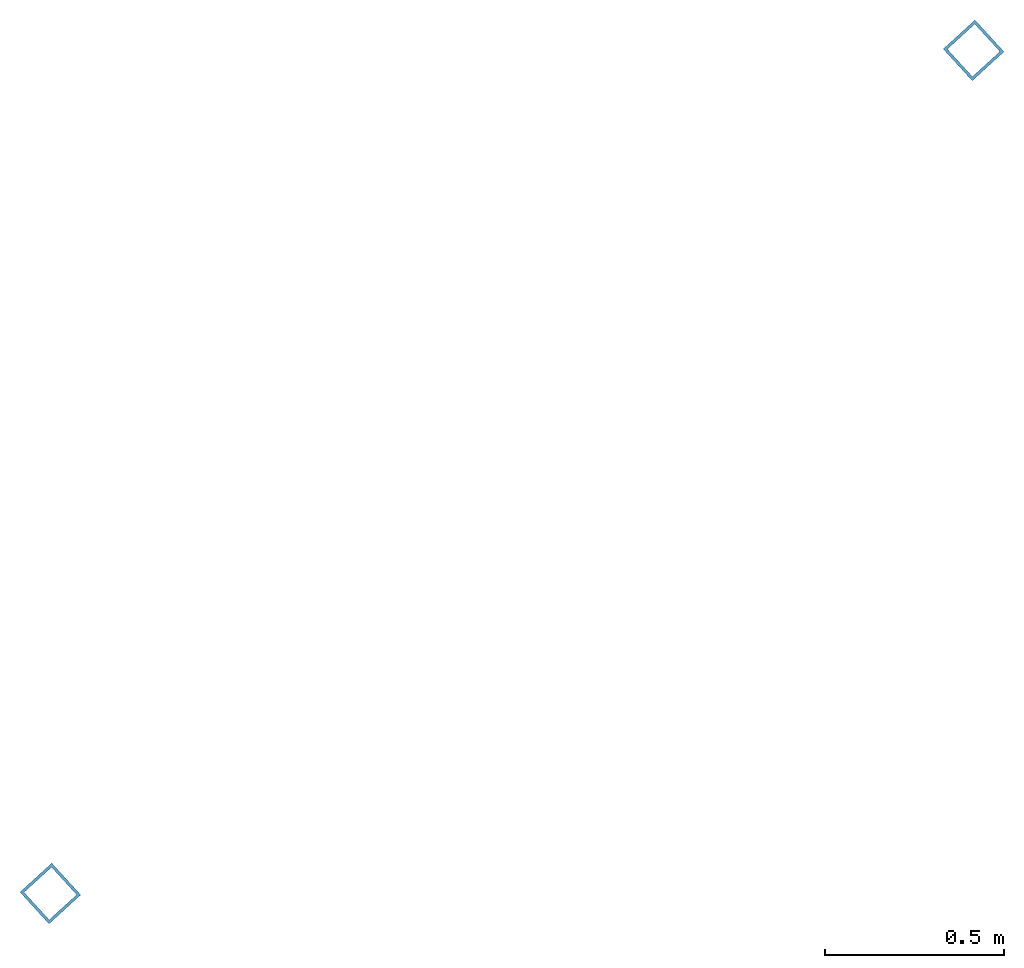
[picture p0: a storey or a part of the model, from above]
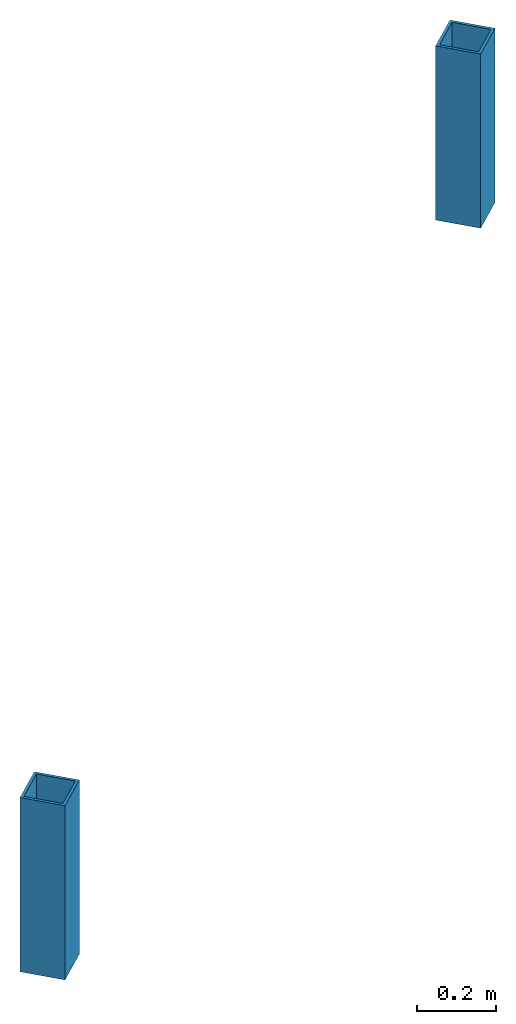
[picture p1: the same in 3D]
Properties of the parts of a building model (IFC2X3)

# File
Description: ViewDefinition [CoordinationView_V2.0, QuantityTakeOffAddOnView]
File name: zv001-a-200-1-0003.ifc (Edited by Naviate Simple BIM 2022 version 6)
Time: 2026-01-09T13:08:05+01:00
Written by: ODA SDAI 24.12
Made in: Autodesk Revit 25.4.30.30 (ENU) - IFC 25.4.0.27

# IfcProject, 10001574
LongName: ENZV Kommersielt areal innland (KAI); Phase: Hovedprosjekt: 01.12.2018

# IfcSite (3)
RefElevation: 0 mm
Name | RefLatitude | RefLongitude | Pset_ProductRequirements, Category
ENZV | 59, 54, 57, 601318 | 10, 44, 59, 999999 | Identity Data - Inventarnr.: ZV001; Building Name: ZV001; CQIncludeDoorSwing: no; CQIncludeRoomNumber: no; CQIncludeRoomNumberWindows: no; CQIncludeWindowSwing: no; Workset: Project Info; Organization Description: BIM 360://Avinor - Stavanger lufthavn/ENZV_ARK_bygg A.rvt; Prosjekt: Stavanger lufthavn, Sola; Text - 02_IfcSite: STAVANGER LUFTHAVN; 01_Modellfil: zv001-a-200-1-0003.rvt; Prosjektleder: Livar Husveg; Tiltaket gjelder: Kommersielt areal innland, KAI; Other - Project Number: 10001574; CQDoorSwingCodes: Left=V;Right=H;notMirrored =L;mirrored =R; Project Issue Date: Tilbudsprosjekt: 22.07.2018; CQWindowSwingCodes: Left=Rettv.;Right=Speilv.; Category: Project Information; Project Address: Enter address here; CQPhaseFilter: Existing:True;New Construction:True;Fase 2.0:True;Fase 3.0:True;Fase 3.9:True;Fase 4.0:True;Fase 5.1:True;Fase 5.2:True;Fase 5.3:True;Fase 5.4:True;Fase 5.9:True;Fase 5.10:True;Fase plot tegninger:True;Fase 6.0:True;; CQIncludeTemporaryDoors: no; Project Name: ENZV Kommersielt areal innland (KAI); Project Status: Hovedprosjekt: 01.12.2018; Tiltakshavers navn: Livar Husveg
2 x Default | 42, 12, 46, 804504 | -71, -1, -58, -789672 | Project Information

# IfcBuilding (3)
Name | NumberOfStoreys | Pset_ProductRequirements, Category
ZV001 | 8 | LongName: ZV001; Identity Data - Inventarnr.: ZV001; Building Name: ZV001; CQIncludeDoorSwing: no; CQIncludeRoomNumber: no; CQIncludeRoomNumberWindows: no; CQIncludeWindowSwing: no; Workset: Project Info; Organization Description: BIM 360://Avinor - Stavanger lufthavn/ENZV_ARK_bygg A.rvt; Prosjekt: Stavanger lufthavn, Sola; Text - 02_IfcSite: STAVANGER LUFTHAVN; 01_Modellfil: zv001-a-200-1-0003.rvt; Prosjektleder: Livar Husveg; Tiltaket gjelder: Kommersielt areal innland, KAI; Other - Project Number: 10001574; CQDoorSwingCodes: Left=V;Right=H;notMirrored =L;mirrored =R; Project Issue Date: Tilbudsprosjekt: 22.07.2018; CQWindowSwingCodes: Left=Rettv.;Right=Speilv.; Category: Project Information; Project Address: Enter address here; CQPhaseFilter: Existing:True;New Construction:True;Fase 2.0:True;Fase 3.0:True;Fase 3.9:True;Fase 4.0:True;Fase 5.1:True;Fase 5.2:True;Fase 5.3:True;Fase 5.4:True;Fase 5.9:True;Fase 5.10:True;Fase plot tegninger:True;Fase 6.0:True;; CQIncludeTemporaryDoors: no; Project Name: ENZV Kommersielt areal innland (KAI); Project Status: Hovedprosjekt: 01.12.2018; Tiltakshavers navn: Livar Husveg
2 x  | 5 | Project Information

# IfcBuildingStorey: Level:8mm Nivåhode Lokale Koter (3)
In: ZV001
Identity Data - Structural: no; Building Story: yes; Workset: Shared Levels and Grids
Graphics(Type) - Line Pattern: Centre; Color: 0; Symbol at End 1 Default: no; Symbol at End 2 Default: yes; Line Weight: 1; Symbol: View - Nivåhode1 : Nivåhode Trekant 2
Identity Data(Type) - Workset: Level Types; Type Name: 8mm Nivåhode Lokale Koter
Constraints(Type) - Elevation Base: Project Base Point
Other - Type Id: 305; Category: Levels; Family and Type: Level: 8mm Nivåhode Lokale Koter; Family: Level; Type: 8mm Nivåhode Lokale Koter
Other(Type) - Category: Levels; Family Name: Level
Phasing - Fagkode: ARK
Name | LongName = Identity Data, Name | Elevation (mm) = Constraints, Elevation (mm) | Pset_AirSideSystemInformation, Name | Pset_AirSideSystemInformation, sets with these values | Etasjekoder | Computation Height (mm)
H01 | H01 | 5100 | H01 | 2 | H01 | 1200
H02 | H02 | 9300 | H02 | 2 | H02 | 0
H03 | H03 | 13200 |  |  | H05 | 0 | Pset_ProductRequirements - Name: H03; sets with these values: 2

# IfcBuildingStorey: Level:_VERKIS-level (6)
Pset_ProductRequirements - Category: Levels
Name | LongName = Pset_AirSideSystemInformation, Name = Pset_ProductRequirements, Name | Elevation (mm)
2 x 1. ETASJE | 1. ETASJE | 5100
2 x 2. ETASJE | 2. ETASJE | 9300
2 x 3. ETASJE | 3. ETASJE | 13200

# IfcBeam: IPE-Beams:IPE220 (4)
Type - Pset_BeamCommon - IsExternal: no; LoadBearing: yes; Reference: IPE220
Type - Pset_ProductRequirements - Category: Structural Framing
Type - Pset_QuantityTakeOff - Reference: IPE220
Type - Pset_ReinforcementBarPitchOfBeam - Reference: IPE220
ePset_LocationTool - Splitting: RESULT
ePset_SimplebimBasicQuantities - Width (Simplebim): 110 mm; Height (Simplebim): 220 mm; Length (Simplebim): 5090 mm
ePset_Simplebim - Assembly Level: Leaf
Pset_QuantityTakeOff - sets with these values: 2
Name (IPE-Beams:IPE220:...) | In | Weight, as steel (Simplebim) (kg) | Volume, net (Simplebim) (m3) | Area, sides, net (Simplebim) (m2)
1845180 | 3. ETASJE | 102.266 | 0.0130276 | 3.58357
1845180 | 3. ETASJE | 106.293 | 0.0135405 | 3.50207
1844115 | 2. ETASJE | 102.266 | 0.0130276 | 3.58357
1844115 | 2. ETASJE | 106.293 | 0.0135405 | 3.50207

# IfcColumn: NO_Column_Steel_Hollow Rectangular:RHS 120x120x8 (8)
Type - PredefinedType: COLUMN; Material: Stål - S355J
Type - Pset_ColumnCommon - IsExternal: no; LoadBearing: yes; Reference: RHS 120x120x8
Type - Pset_ProductRequirements - Category: Structural Columns
Type - Pset_QuantityTakeOff - Reference: RHS 120x120x8
Type - Pset_ReinforcementBarPitchOfColumn - Reference: RHS 120x120x8
ePset_SimplebimBasicQuantities - Width (Simplebim): 120 mm; Depth (Simplebim): 120 mm
ePset_Simplebim - Assembly Level: Leaf
Pset_QuantityTakeOff - sets with these values: 2
Name (NO_Column_Steel_Hollow Rectangular:RHS 120x120x8:...) | In | Weight, as steel (Simplebim) (kg) | Volume, net (Simplebim) (m3) | Height (Simplebim) (mm) | Area, sides, net (Simplebim) (m2) | Splitting
1844919 | 2. ETASJE | 112.313 | 0.0143073 | 3992 | 3.57683 | ORIGINAL
1844921 | 2. ETASJE | 112.313 | 0.0143073 | 3992 | 3.57683 | ORIGINAL
1844919 | 2. ETASJE | 107.059 | 0.0136381 | 3992 | 3.41167 | ORIGINAL
1844921 | 2. ETASJE | 107.059 | 0.0136381 | 3992 | 3.41167 | ORIGINAL
1840977 | 1. ETASJE | 15.1926 | 0.00193536 | 540 | 0.48384 | RESULT
1840979 | 1. ETASJE | 15.1926 | 0.00193536 | 540 | 0.48384 | RESULT
1840977 | 1. ETASJE | 14.482 | 0.00184484 | 540 | 0.461498 | RESULT
1840979 | 1. ETASJE | 14.482 | 0.00184484 | 540 | 0.461498 | RESULT

# IfcColumn: Søyle Betong Sirkulær:350 (3)
In: H02
Type - PredefinedType: COLUMN; Material: Betong Plasstøpt - B35
Type - Other - Category: Structural Columns; Family Name: Søyle Betong Sirkulær; k1: 3.14159
Type - Dimensions - D: 350 mm; Perimeter: 1099.56 mm
Type - Identity Data - Type Name: 350; URL: www.cad-q.no; Workset: Family : Structural Columns : Søyle Betong Sirkulær
Type - Structural - Section Shape: 0
Type - Pset_ColumnCommon - LoadBearing: yes
Phasing - Phase Created: Fase 1 - Som bygget
Pset_QuantityTakeOff - Reference: 350; sets with these values: 2
Pset_ColumnCommon - IsExternal: no; Reference: 350
Identity Data - Has Association: yes; Workset: Workset1
Dimensions - Volume: 0.322292 m3; Length: 3350 mm
Other - Family and Type: Søyle Betong Sirkulær: 350; Type Id: 414188; Family: Søyle Betong Sirkulær; Type: 350
ePset_LocationTool - Splitting: ORIGINAL
ePset_SimplebimBasicQuantities - Height (Simplebim): 3350 mm; Depth (Simplebim): 350 mm; Width (Simplebim): 350 mm; Volume, net (Simplebim): 0.320674 m3; Weight, as steel (Simplebim): 2517.29 kg; Area, sides, net (Simplebim): 3.67884 m2
Structural - Rebar Cover - Top Face: Rebar Cover 1 <25 mm>; Rebar Cover - Other Faces: Rebar Cover 1 <25 mm>; Rebar Cover - Bottom Face: Rebar Cover 1 <25 mm>
ePset_Simplebim - Assembly Level: Leaf
Materials and Finishes - Structural Material: Betong Plasstøpt - B35
Constraints - Top Offset: -550 mm; Room Bounding: yes; Base Offset: 0 mm; Moves With Grids: yes; Base Level: H02; Level: H02; Top Level: H03; Column Style: Vertical
BaseQuantities - NetVolume: 0.322292 m3; OuterSurfaceArea: 3.68352 m2; CrossSectionArea: 0.0961984 m2; Length: 3350 mm; GrossVolume: 0.322265 m3
Name (Søyle Betong Sirkulær:350:...) | Column Location Mark
548730 | L-164
548803 | L-162
548818 | L-160

# IfcColumn: Søyle Betong Sirkulær:450 (3)
In: H01
Type - PredefinedType: COLUMN; Material: Betong Plasstøpt - B35
Type - Other - Category: Structural Columns; Family Name: Søyle Betong Sirkulær; k1: 3.14159
Type - Dimensions - D: 450 mm; Perimeter: 1413.72 mm
Type - Identity Data - Type Name: 450; URL: www.cad-q.no; Workset: Family : Structural Columns : Søyle Betong Sirkulær
Type - Structural - Section Shape: 0
Type - Pset_ColumnCommon - LoadBearing: yes
Phasing - Phase Created: Fase 1 - Som bygget
Identity Data - Has Association: yes; Workset: Workset1
Other - Family and Type: Søyle Betong Sirkulær: 450; Type Id: 958864; Family: Søyle Betong Sirkulær; Type: 450
Structural - Rebar Cover - Top Face: Rebar Cover 1 <25 mm>; Rebar Cover - Other Faces: Rebar Cover 1 <25 mm>; Rebar Cover - Bottom Face: Rebar Cover 1 <25 mm>
Constraints - Room Bounding: yes; Moves With Grids: yes; Level: H01; Base Level: H01; Top Level: H02; Column Style: Vertical
ePset_LocationTool - Splitting: RESULT
ePset_Simplebim - Assembly Level: Leaf
Materials and Finishes - Structural Material: Betong Plasstøpt - B35
ePset_SimplebimBasicQuantities - Area, sides, net (Simplebim): 0.635365 m2; Volume, net (Simplebim): 0.0712066 m3; Weight, as steel (Simplebim): 558.972 kg; Height (Simplebim): 450 mm; Width (Simplebim): 450 mm; Depth (Simplebim): 450 mm
Pset_ColumnCommon - IsExternal: no; Reference: 450
Pset_ReinforcementBarPitchOfColumn - Reference: 450; sets with these values: 2
Name (Søyle Betong Sirkulær:450:...) | Column Location Mark
958997 | L-160
959023 | L-164
959010 | L-162

# IfcSlab: Floor:Standard 550mm (2)
Type - PredefinedType: FLOOR; Material: <Unnamed> 550 mm
Type - Other - Category: Floors; Family Name: Floor
Type - Construction - Function: Interior; Default Thickness: 550 mm
Type - Graphics - Coarse Scale Fill Color: 0
Type - Identity Data - Type Name: Standard 550mm; Workset: Floor Types
Type - Analytical Properties - Absorptance: 0.1; Roughness: 1
Other - Type: Standard 550mm; Type Id: 388455; Family and Type: Floor: Standard 550mm; Family: Floor
Pset_QuantityTakeOff - Reference: Standard 550mm; sets with these values: 2
Pset_SlabCommon - LoadBearing: no; IsExternal: no; Reference: Standard 550mm
ePset_LocationTool - Splitting: RESULT
Identity Data - Has Association: no; Workset: Workset1
Phasing - Phase Created: Fase 1 - Som bygget
ePset_SimplebimBasicQuantities - Area, sides, net (Simplebim): 28.5518 m2; Perimeter (Simplebim): 51912.3 mm; Area, top, net (Simplebim): 115.915 m2; Volume, net (Simplebim): 63.7533 m3; Area, largest surface, net (Simplebim): 115.915 m2; Thickness (Simplebim): 550 mm
Constraints - Related to Mass: no; Room Bounding: yes
ePset_Simplebim - Assembly Level: Leaf
Structural - Structural: no
Name (Floor:Standard 550mm:...) | In | Level
566137 | H02 | H02
632864 | H03 | H03

# IfcSlab: Floor:Standard 560mm, Floor:Standard 560mm:3043193
In: H02
Type - PredefinedType: FLOOR; Material: <Unnamed> 560 mm
Type - Other - Category: Floors; Family Name: Floor
Type - Construction - Function: Interior; Default Thickness: 560 mm
Type - Graphics - Coarse Scale Fill Color: 0
Type - Identity Data - Type Name: Standard 560mm; Workset: Floor Types
Type - Analytical Properties - Absorptance: 0.1; Roughness: 1
Pset_ReinforcementBarPitchOfSlab - Reference: Standard 560mm; sets with these values: 2
Pset_SlabCommon - LoadBearing: no; IsExternal: no; Reference: Standard 560mm
Identity Data - Has Association: no; Workset: Workset1
Other - Type Id: 638814; Family and Type: Floor: Standard 560mm; Type: Standard 560mm; Family: Floor
Phasing - Phase Created: Fase 1 - Som bygget
ePset_SimplebimBasicQuantities - Area, top, net (Simplebim): 115.915 m2; Area, largest surface, net (Simplebim): 115.915 m2; Thickness (Simplebim): 560 mm; Perimeter (Simplebim): 51912.3 mm; Volume, net (Simplebim): 64.9124 m3; Area, sides, net (Simplebim): 29.0709 m2
Constraints - Related to Mass: no; Room Bounding: yes; Level: H02
ePset_Simplebim - Assembly Level: Leaf
Structural - Structural: no
ePset_LocationTool - Splitting: RESULT

# IfcSlab: Floor:Ståldekke 128 (2)
In: 3. ETASJE
Type - PredefinedType: FLOOR; Material: NO_Metall - Stål(2) 128 mm
Type - Pset_ElementShading - Roughness: 304.8 mm
Type - Pset_ProductRequirements - Category: Floors
Type - Pset_QuantityTakeOff - Reference: Ståldekke 128
Type - Pset_ReinforcementBarPitchOfSlab - Description: Ståldekke; Reference: Ståldekke 128
Type - Pset_SlabCommon - Reference: Ståldekke 128; IsExternal: no
ePset_SimplebimBasicQuantities - Area, sides, net (Simplebim): 1.3372 m2; Area, top, net (Simplebim): 0.686474 m2; Volume, net (Simplebim): 0.0878688 m3; Perimeter (Simplebim): 10446.9 mm; Area, largest surface, net (Simplebim): 0.686475 m2; Thickness (Simplebim): 128 mm
Pset_SlabCommon - LoadBearing: yes
ePset_LocationTool - Splitting: RESULT
ePset_Simplebim - Assembly Level: Leaf

# IfcWall: Basic Wall:IV Eks-96 mm_70 mm stålstender+1*13 mm gips hver side (2)
In: H02
Type - PredefinedType: STANDARD; Material: Vegg 13 mm, Vegg 70 mm, Vegg 13 mm
Type - Other - Category: Walls; Family Name: Basic Wall
Type - Construction - Function: Exterior; Width: 96 mm; Wrapping at Inserts: Do not wrap
Type - Graphics - Coarse Scale Fill Color: 12632256; Coarse Scale Fill Pattern: <Solid fill>
Type - Identity Data - Type Name: IV Eks-96 mm_70 mm stålstender+1*13 mm gips hver side; Workset: Wall Types; Type Mark: Eksisterende
Type - Analytical Properties - Absorptance: 0.1; Roughness: 1
Phasing - Phase Created: Fase 1 - Som bygget
Pset_WallCommon - IsExternal: yes; ExtendToStructure: no; LoadBearing: no; Reference: IV Eks-96 mm_70 mm stålstender+1*13 mm gips hver side
ePset_LocationTool - Splitting: RESULT
Constraints - Top Constraint: Up to level: H03; Base is Attached: no; Related to Mass: no; Room Bounding: yes; Top is Attached: no; Base Constraint: H02; Location Line: Finish Face: Interior
Cross-Section Definition - Cross-Section: Vertical
Structural - Structural Usage: Non-bearing; Structural: no
Pset_QuantityTakeOff - Reference: IV Eks-96 mm_70 mm stålstender+1*13 mm gips hver side; sets with these values: 2
Identity Data - Workset: Workset1
ePset_Simplebim - Assembly Level: Leaf
Other - Family: Basic Wall; Type: IV Eks-96 mm_70 mm stålstender+1*13 mm gips hver side; Family and Type: Basic Wall: IV Eks-96 mm_70 mm stålstender+1*13 mm gips hver side; Type Id: 1363173
Name (Basic Wall:IV Eks-96 mm_70 mm stålstender+1*13 mm gips hver side:...) | Area, largest surface, net (Simplebim) (m2) | Volume, net (Simplebim) (m3)
510428 | 6.9048 | 0.662858 | ePset_SimplebimBasicQuantities - Area, side, net, smaller (Simplebim): 6.90474 m2; Area, side, gross, AABB (Simplebim): 6.90435 m2; Area, side, net, average (Simplebim): 6.90477 m2; Area, side, gross, average (Simplebim): 9.03587 m2; Area, side, net, larger (Simplebim): 6.9048 m2; Area, side, gross, smaller (Simplebim): 9.03584 m2; Thickness (Simplebim): 96 mm; Length (Simplebim): 2061 mm; Height (Simplebim): 3350 mm; Area, side, gross, larger (Simplebim): 9.0359 m2
510471 | 1.43029 | 0.0899561 | Dimensions - Keep Concentric: yes; Graphics - Center Mark Visible: no

# IfcWallStandardCase: Basic Wall:IV Eks-96 mm_70 mm stålstender+1*13 mm gips hver side, Basic Wall:IV Eks-96 mm_70 mm stålstender+1*13 mm gips hver side:510463
In: H02
Type - PredefinedType: STANDARD; Material: Vegg 13 mm, Vegg 70 mm, Vegg 13 mm
Type - Other - Category: Walls; Family Name: Basic Wall
Type - Construction - Function: Exterior; Width: 96 mm; Wrapping at Inserts: Do not wrap
Type - Graphics - Coarse Scale Fill Color: 12632256; Coarse Scale Fill Pattern: <Solid fill>
Type - Identity Data - Type Name: IV Eks-96 mm_70 mm stålstender+1*13 mm gips hver side; Workset: Wall Types; Type Mark: Eksisterende
Type - Analytical Properties - Absorptance: 0.1; Roughness: 1
Phasing - Phase Created: Fase 1 - Som bygget
ePset_SimplebimBasicQuantities - Area, side, net, larger (Simplebim): 35.4719 m2; Area, side, gross, larger (Simplebim): 35.4719 m2; Area, largest surface, net (Simplebim): 35.4719 m2; Area, side, net, average (Simplebim): 35.4718 m2; Area, side, gross, average (Simplebim): 35.4718 m2; Area, side, gross, AABB (Simplebim): 35.4719 m2; Area, side, net, smaller (Simplebim): 35.4718 m2; Area, side, gross, smaller (Simplebim): 35.4718 m2; Volume, net (Simplebim): 3.4053 m3; Length (Simplebim): 10588.6 mm; Thickness (Simplebim): 96 mm; Height (Simplebim): 3350 mm
Dimensions - Area: 35.4719 m2; Length: 10636.6 mm; Volume: 3.4053 m3
Pset_WallCommon - IsExternal: yes; ExtendToStructure: no; LoadBearing: no; Reference: IV Eks-96 mm_70 mm stålstender+1*13 mm gips hver side
Constraints - Unconnected Height: 3350 mm; Top Offset: -550 mm; Top Constraint: Up to level: H03; Base Extension Distance: 0 mm; Base is Attached: no; Base Offset: 0 mm; Related to Mass: no; Room Bounding: yes; Top Extension Distance: 0 mm; Top is Attached: no; Base Constraint: H02; Location Line: Finish Face: Interior
Cross-Section Definition - Cross-Section: Vertical
Structural - Structural Usage: Non-bearing; Structural: no
ePset_LocationTool - Splitting: ORIGINAL
Pset_QuantityTakeOff - Reference: IV Eks-96 mm_70 mm stålstender+1*13 mm gips hver side; sets with these values: 2
Identity Data - Workset: Workset1
ePset_Simplebim - Assembly Level: Leaf
Other - Family: Basic Wall; Type: IV Eks-96 mm_70 mm stålstender+1*13 mm gips hver side; Family and Type: Basic Wall: IV Eks-96 mm_70 mm stålstender+1*13 mm gips hver side; Type Id: 1363173
BaseQuantities - GrossSideArea: 35.4719 m2; NetSideArea: 35.4719 m2; GrossFootprintArea: 1.01651 m2; NetVolume: 3.4053 m3; Length: 10588.6 mm; Width: 96 mm; Height: 3350 mm; GrossVolume: 3.4053 m3

# IfcWallStandardCase: Basic Wall:Standard - 150mm (3)
In: H02
Type - PredefinedType: STANDARD; Material: Vegg 150 mm
Type - Other - Category: Walls; Family Name: Basic Wall
Type - Construction - Function: Exterior; Width: 150 mm; Wrapping at Inserts: Do not wrap
Type - Graphics - Coarse Scale Fill Color: 12632256; Coarse Scale Fill Pattern: <Solid fill>
Type - Identity Data - Type Name: Standard - 150mm; Workset: Wall Types
Type - Analytical Properties - Absorptance: 0.1; Roughness: 1
Phasing - Phase Created: Fase 1 - Som bygget
ePset_LocationTool - Splitting: ORIGINAL
Constraints - Unconnected Height: 3350 mm; Base Extension Distance: 0 mm; Base is Attached: no; Base Offset: 0 mm; Related to Mass: no; Room Bounding: yes; Top Extension Distance: 0 mm; Top is Attached: no; Base Constraint: H02; Location Line: Finish Face: Interior
Cross-Section Definition - Cross-Section: Vertical
Structural - Structural Usage: Non-bearing; Structural: no
Identity Data - Workset: Workset1
ePset_SimplebimBasicQuantities - Thickness (Simplebim): 150 mm; Height (Simplebim): 3350 mm
Other - Family: Basic Wall; Family and Type: Basic Wall: Standard - 150mm; Type Id: 129062; Type: Standard - 150mm
Pset_QuantityTakeOff - Reference: Standard - 150mm; sets with these values: 2
ePset_Simplebim - Assembly Level: Leaf
Pset_WallCommon - IsExternal: yes; ExtendToStructure: no; LoadBearing: no; Reference: Standard - 150mm
BaseQuantities - Width: 150 mm; Height: 3350 mm
Name (Basic Wall:Standard - 150mm:...) | Top Offset (mm) | Area, side, gross, AABB (Simplebim) (m2) = Area, side, net, smaller (Simplebim) (m2) = Area, side, gross, smaller (Simplebim) (m2) = Area, side, net, larger (Simplebim) (m2) = Area, side, gross, larger (Simplebim) (m2) = Area, side, gross, average (Simplebim) (m2) = Area, side, net, average (Simplebim) (m2) = Area, largest surface, net (Simplebim) (m2) | Volume, net (Simplebim) (m3) | Length (Simplebim) (mm) = BaseQuantities, Length (mm) | Area (m2) = NetSideArea (m2) = GrossSideArea (m2) | Dimensions, Length (mm) | Volume (m3) = NetVolume (m3) | GrossVolume (m3) | GrossFootprintArea (m2)
531061 | -550 | 29.3913 | 4.40869 | 8773.51 | 29.3913 | 8746.51 | 4.40869 | 4.40869 | 1.31603 | Constraints - Top Constraint: Up to level: H03
901176 | 0 | 9.2929 | 1.39394 | 2774 | 9.2929 | 2849 | 1.39393 | 1.39394 | 0.4161
2475116 | 0 | 9.2929 | 1.39394 | 2774 | 9.29289 | 2849 | 1.39393 | 1.39393 | 0.4161

# IfcWallStandardCase: Basic Wall:Standard - 152mm, Basic Wall:Standard - 152mm:510175
In: H02
Type - PredefinedType: STANDARD; Material: Vegg 152 mm
Type - Other - Category: Walls; Family Name: Basic Wall
Type - Construction - Function: Exterior; Width: 152 mm; Wrapping at Inserts: Do not wrap
Type - Graphics - Coarse Scale Fill Color: 12632256; Coarse Scale Fill Pattern: <Solid fill>
Type - Identity Data - Type Name: Standard - 152mm; Workset: Wall Types
Type - Analytical Properties - Absorptance: 0.1; Roughness: 1
Phasing - Phase Created: Fase 1 - Som bygget
Pset_ReinforcementBarPitchOfWall - Reference: Standard - 152mm; sets with these values: 2
Constraints - Unconnected Height: 3350 mm; Top Offset: -550 mm; Top Constraint: Up to level: H03; Base Extension Distance: 0 mm; Base is Attached: no; Base Offset: 0 mm; Related to Mass: no; Room Bounding: yes; Top Extension Distance: 0 mm; Top is Attached: no; Base Constraint: H02; Location Line: Finish Face: Interior
Cross-Section Definition - Cross-Section: Vertical
Structural - Structural Usage: Non-bearing; Structural: no
Dimensions - Length: 6599.96 mm; Area: 22.6191 m2; Volume: 3.4381 m3
Identity Data - Workset: Workset1
ePset_LocationTool - Splitting: ORIGINAL
ePset_Simplebim - Assembly Level: Leaf
Other - Type: Standard - 152mm; Type Id: 452378; Family: Basic Wall; Family and Type: Basic Wall: Standard - 152mm
ePset_SimplebimBasicQuantities - Area, side, gross, AABB (Simplebim): 22.6191 m2; Area, side, net, smaller (Simplebim): 22.6191 m2; Area, side, gross, larger (Simplebim): 22.6191 m2; Area, side, gross, smaller (Simplebim): 22.6191 m2; Area, side, net, larger (Simplebim): 22.6191 m2; Area, side, net, average (Simplebim): 22.6191 m2; Area, largest surface, net (Simplebim): 22.6191 m2; Area, side, gross, average (Simplebim): 22.6191 m2; Volume, net (Simplebim): 3.4381 m3; Length (Simplebim): 6751.97 mm; Thickness (Simplebim): 152 mm; Height (Simplebim): 3350 mm
Pset_WallCommon - Reference: Standard - 152mm; IsExternal: yes; ExtendToStructure: no; LoadBearing: no
BaseQuantities - GrossFootprintArea: 1.0263 m2; NetSideArea: 22.6191 m2; GrossSideArea: 22.6191 m2; GrossVolume: 3.4381 m3; NetVolume: 3.4381 m3; Length: 6751.97 mm; Width: 152 mm; Height: 3350 mm
